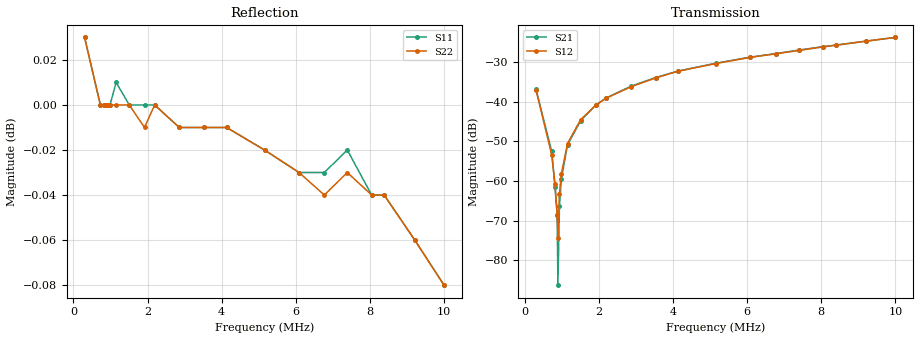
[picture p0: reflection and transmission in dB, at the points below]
!s-Parameter Generated by FASTRON Sdn. Bhd.
!FASTRON P/N : 1812AFTC-342X
!Keysight Technologies: E5071C_MY46733604_B.14.02
!Date: Wed Mar 18 14:01:19 2026
!Version  :Rev00  Wed Mar 18 14:01:19 2026
!Data & Calibration Information:
!Freq  S11:SOLT2(ON)  S21:SOLT2(ON)  S12:SOLT2(ON)  S22:SOLT2(ON)
!PortZ  Port1:50+j0  Port2:50+j0
!When reading reference impedance value at option line is always used.
! Remarks : This data is being provided solely for informational purposes.
# Hz S dB R 50
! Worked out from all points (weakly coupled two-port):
!   1601 points, 300 kHz to 10 MHz, reference 50 ohm
!   highest |S21| = -23.78 dB at 10 MHz (marker M1); lowest = -86.3 dB at 892.5 kHz (marker M2)
!   lowest |S11| = -0.1 dB at 10 MHz (marker M3), VSWR 213.54, Z = 3.94 - j199 ohm
!   |S11| at or under -10 dB: nowhere
!   |S22| runs from -0.1 to 0.0 dB; largest |S21 - S12| = 0.00086
!   S11 on the Smith chart (normalised r, x): 300 kHz: -0, +11; 2.19 MHz: 0.00, +1.36; 4.134 MHz: 0.00, +0.39; 6.088 MHz: 0.00, -0.20; 8.047 MHz: 0.00, -0.95; 10 MHz: 0.08, -3.98
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300000  0.03 10.6  -36.85 -87.6  -36.94 -87.1  0.03 -10.5
725834  0.00 24.3  -52.50 -86.3  -53.40 -83.6  -0.00 -26.7
813962  0.00 27.2  -61.40 -76.0  -60.70 -69.5  0.00 -30.0
874394  0.00 29.2  -68.67 -37.7  -68.53 -16.1  0.00 -32.2
892524  -0.00 29.8  -86.25 -95.0  -74.24 68.5  -0.00 -32.9
934827  0.00 31.2  -66.41 64.5  -63.19 70.0  -0.00 -34.4
985187  0.00 32.9  -59.48 78.4  -58.19 75.3  -0.00 -36.3
1151751  0.01 38.4  -50.93 86.7  -50.55 80.4  -0.00 -42.5
1505896  0.00 50.1  -44.79 81.3  -44.51 82.8  -0.00 -55.6
1917564  -0.00 63.8  -40.80 83.0  -40.87 84.7  -0.01 -70.9
2189863  -0.00 72.8  -39.11 83.9  -39.12 83.9  -0.00 -81.0
2856713  -0.01 94.9  -36.10 82.9  -36.27 82.8  -0.01 -105.7
3534704  -0.01 117.4  -33.89 80.6  -33.98 80.9  -0.01 -130.8
4133799  -0.01 137.3  -32.27 79.4  -32.32 79.5  -0.01 -153.0
5155786  -0.02 171.2  -30.28 77.5  -30.37 77.4  -0.02 169.2
6087954  -0.03 -157.8  -28.75 74.2  -28.80 74.2  -0.03 134.7
6770355  -0.03 -135.1  -27.87 73.4  -27.92 73.4  -0.04 109.5
7390266  -0.02 -114.6  -26.98 72.3  -27.07 72.4  -0.03 86.5
8047393  -0.04 -92.8  -26.11 70.8  -26.17 70.9  -0.04 62.1
8385344  -0.04 -81.7  -25.73 70.0  -25.76 70.0  -0.04 49.5
9211447  -0.06 -54.3  -24.71 67.5  -24.72 67.4  -0.06 18.9
1e7  -0.08 -28.2  -23.78 64.2  -23.77 64.3  -0.08 -10.4
